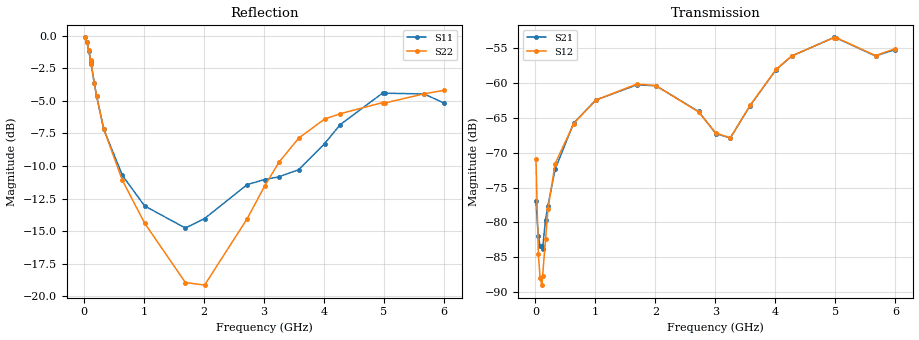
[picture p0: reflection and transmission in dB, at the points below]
!Agilent Technologies,N5230A,MY45001650,A.07.50.48
!Agilent N5230A: A.07.50.48
!Date: Saturday, July 08, 2017 15:49:37
!Correction: S11(Full 2 Port(1,2))
!S21(Full 2 Port(1,2))
!S12(Full 2 Port(1,2))
!S22(Full 2 Port(1,2))
!S2P File: Measurements: S11, S21, S12, S22:
# Hz S  dB  R 50
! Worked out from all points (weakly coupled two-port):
!   600 points, 10 MHz to 6 GHz, reference 50 ohm
!   highest |S21| = -53.49 dB at 4.98 GHz (marker M1); lowest = -83.8 dB at 120 MHz (marker M2)
!   lowest |S11| = -14.8 dB at 1.69 GHz (marker M3), VSWR 1.45, Z = 34.6 + j1.18 ohm
!   |S11| at or under -10 dB: 553.6 MHz to 3.663 GHz (3.109 GHz wide, 147 % of centre)
!   |S22| runs from -19.6 to -0.1 dB; largest |S21 - S12| = 0.00041
!   S11 on the Smith chart (normalised r, x): 10 MHz: 3, -20; 110 MHz: 0.52, -1.89; 330 MHz: 0.55, -0.56; 2.72 GHz: 0.58, +0.09; 4.27 GHz: 1.39, +1.14; 6 GHz: 2.58, -1.42
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1e7  -0.11 -5.7  -76.96 167.3  -70.86 26.2  -0.11 -5.5
5e7  -0.50 -26.6  -82.01 29.0  -84.53 61.0  -0.48 -25.4
8e7  -1.13 -40.8  -83.44 -7.2  -88.03 -30.0  -1.10 -38.9
1.1e8  -1.91 -53.1  -83.35 69.5  -88.98 -76.4  -1.88 -50.6
1.2e8  -2.17 -56.7  -83.81 118.2  -87.72 -101.0  -2.15 -53.9
1.7e8  -3.61 -73.0  -79.60 131.6  -82.44 125.5  -3.58 -69.4
2.1e8  -4.63 -83.7  -77.58 123.6  -78.14 118.3  -4.60 -79.5
3.3e8  -7.18 -109.0  -72.37 98.1  -71.58 101.3  -7.18 -101.8
6.4e8  -10.72 -148.5  -65.75 64.6  -65.83 65.8  -11.10 -134.9
1.01e9  -13.07 -172.5  -62.46 37.6  -62.46 37.8  -14.39 -154.8
1.69e9  -14.77 174.8  -60.30 -10.3  -60.18 -10.4  -18.96 -170.6
2.01e9  -14.04 177.0  -60.42 -34.5  -60.39 -33.4  -19.16 -169.6
2.72e9  -11.43 163.9  -64.10 -97.2  -64.18 -97.2  -14.05 177.0
3.01e9  -11.04 149.4  -67.29 -142.9  -67.21 -143.4  -11.55 168.4
3.25e9  -10.83 133.3  -67.90 160.5  -67.87 160.8  -9.71 161.5
3.58e9  -10.28 105.3  -63.25 93.1  -63.21 93.4  -7.85 153.0
4.01e9  -8.28 64.2  -58.14 43.5  -58.09 43.5  -6.39 139.8
4.27e9  -6.82 45.7  -56.18 19.0  -56.15 19.1  -5.98 131.5
4.98e9  -4.38 14.4  -53.49 -42.6  -53.51 -42.5  -5.12 103.8
5.01e9  -4.40 13.1  -53.55 -45.4  -53.52 -45.3  -5.16 102.3
5.67e9  -4.46 -7.2  -56.15 -77.2  -56.09 -77.1  -4.45 69.8
6e9  -5.16 -20.4  -55.24 -78.3  -55.10 -78.9  -4.18 52.3
